VERSION 5.7 ;
  NOWIREEXTENSIONATPIN ON ;
  DIVIDERCHAR "/" ;
  BUSBITCHARS "[]" ;
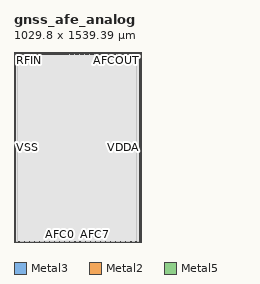
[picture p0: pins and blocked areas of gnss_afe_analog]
MACRO gnss_afe_analog
  CLASS BLOCK ;
  FOREIGN gnss_afe_analog ;
  ORIGIN 0.000 0.000 ;
  SIZE 1029.800 BY 1539.395 ;
  PIN VSS
    DIRECTION INOUT ;
    USE GROUND ;
    PORT
      LAYER Metal3 ;
        RECT 6.000 6.000 9.000 1533.395 ;
    END
    PORT
      LAYER Metal2 ;
        RECT 436.440 1533.295 445.940 1539.395 ;
    END
    PORT
      LAYER Metal2 ;
        RECT 423.290 1533.295 433.540 1539.395 ;
    END
    PORT
      LAYER Metal2 ;
        RECT 411.440 1533.295 421.690 1539.395 ;
    END
    PORT
      LAYER Metal2 ;
        RECT 397.910 1533.295 408.160 1539.395 ;
    END
    PORT
      LAYER Metal2 ;
        RECT 386.060 1533.295 396.310 1539.395 ;
    END
    PORT
      LAYER Metal2 ;
        RECT 373.660 1533.295 383.160 1539.395 ;
    END
    PORT
      LAYER Metal2 ;
        RECT 228.440 1533.295 237.940 1539.395 ;
    END
    PORT
      LAYER Metal2 ;
        RECT 215.290 1533.295 225.540 1539.395 ;
    END
    PORT
      LAYER Metal2 ;
        RECT 203.440 1533.295 213.690 1539.395 ;
    END
    PORT
      LAYER Metal2 ;
        RECT 189.910 1533.295 200.160 1539.395 ;
    END
    PORT
      LAYER Metal2 ;
        RECT 178.060 1533.295 188.310 1539.395 ;
    END
    PORT
      LAYER Metal2 ;
        RECT 165.660 1533.295 175.160 1539.395 ;
    END
    PORT
      LAYER Metal2 ;
        RECT 20.440 1533.295 29.940 1539.395 ;
    END
    PORT
      LAYER Metal2 ;
        RECT 7.290 1533.295 17.540 1539.395 ;
    END
    PORT
      LAYER Metal5 ;
        RECT 6.000 1530.395 1023.800 1533.395 ;
    END
  END VSS
  PIN VDDA
    DIRECTION INOUT ;
    USE POWER ;
    PORT
      LAYER Metal3 ;
        RECT 1020.800 6.000 1023.800 1533.395 ;
    END
    PORT
      LAYER Metal2 ;
        RECT 332.440 1524.295 341.940 1539.395 ;
    END
    PORT
      LAYER Metal2 ;
        RECT 319.290 1524.295 329.540 1539.395 ;
    END
    PORT
      LAYER Metal2 ;
        RECT 307.440 1524.295 317.690 1539.395 ;
    END
    PORT
      LAYER Metal2 ;
        RECT 293.910 1524.295 304.160 1539.395 ;
    END
    PORT
      LAYER Metal2 ;
        RECT 282.060 1524.295 292.310 1539.395 ;
    END
    PORT
      LAYER Metal2 ;
        RECT 269.660 1524.295 279.160 1539.395 ;
    END
    PORT
      LAYER Metal5 ;
        RECT 6.000 1521.395 45.500 1524.395 ;
    END
    PORT
      LAYER Metal5 ;
        RECT 56.500 1521.395 85.500 1524.395 ;
    END
    PORT
      LAYER Metal5 ;
        RECT 96.500 1521.395 125.500 1524.395 ;
    END
    PORT
      LAYER Metal5 ;
        RECT 136.500 1521.395 165.500 1524.395 ;
    END
    PORT
      LAYER Metal5 ;
        RECT 176.500 1521.395 205.500 1524.395 ;
    END
    PORT
      LAYER Metal5 ;
        RECT 216.500 1521.395 245.500 1524.395 ;
    END
    PORT
      LAYER Metal5 ;
        RECT 256.500 1521.395 285.500 1524.395 ;
    END
    PORT
      LAYER Metal5 ;
        RECT 296.500 1521.395 325.500 1524.395 ;
    END
    PORT
      LAYER Metal5 ;
        RECT 336.500 1521.395 365.500 1524.395 ;
    END
    PORT
      LAYER Metal5 ;
        RECT 376.500 1521.395 405.500 1524.395 ;
    END
    PORT
      LAYER Metal5 ;
        RECT 416.500 1521.395 445.500 1524.395 ;
    END
    PORT
      LAYER Metal5 ;
        RECT 456.500 1521.395 485.500 1524.395 ;
    END
    PORT
      LAYER Metal5 ;
        RECT 496.500 1521.395 525.500 1524.395 ;
    END
    PORT
      LAYER Metal5 ;
        RECT 536.500 1521.395 565.500 1524.395 ;
    END
    PORT
      LAYER Metal5 ;
        RECT 576.500 1521.395 605.500 1524.395 ;
    END
    PORT
      LAYER Metal5 ;
        RECT 616.500 1521.395 645.500 1524.395 ;
    END
    PORT
      LAYER Metal5 ;
        RECT 656.500 1521.395 665.500 1524.395 ;
    END
    PORT
      LAYER Metal5 ;
        RECT 676.500 1521.395 685.500 1524.395 ;
    END
    PORT
      LAYER Metal5 ;
        RECT 696.500 1521.395 725.500 1524.395 ;
    END
    PORT
      LAYER Metal5 ;
        RECT 736.500 1521.395 745.500 1524.395 ;
    END
    PORT
      LAYER Metal5 ;
        RECT 756.500 1521.395 765.500 1524.395 ;
    END
    PORT
      LAYER Metal5 ;
        RECT 776.500 1521.395 805.500 1524.395 ;
    END
    PORT
      LAYER Metal5 ;
        RECT 816.500 1521.395 825.500 1524.395 ;
    END
    PORT
      LAYER Metal5 ;
        RECT 836.500 1521.395 845.500 1524.395 ;
    END
    PORT
      LAYER Metal5 ;
        RECT 856.500 1521.395 885.500 1524.395 ;
    END
    PORT
      LAYER Metal5 ;
        RECT 896.500 1521.395 905.500 1524.395 ;
    END
    PORT
      LAYER Metal5 ;
        RECT 916.500 1521.395 925.500 1524.395 ;
    END
    PORT
      LAYER Metal5 ;
        RECT 936.500 1521.395 965.500 1524.395 ;
    END
    PORT
      LAYER Metal5 ;
        RECT 976.500 1521.395 985.500 1524.395 ;
    END
    PORT
      LAYER Metal5 ;
        RECT 996.500 1521.395 1023.800 1524.395 ;
    END
  END VDDA
  PIN RFIN
    DIRECTION INOUT ;
    USE SIGNAL ;
    ANTENNADIFFAREA 33.599998 ;
    PORT
      LAYER Metal2 ;
        RECT 75.640 1537.395 119.960 1539.395 ;
    END
  END RFIN
  PIN VDDV
    DIRECTION INOUT ;
    USE POWER ;
    PORT
      LAYER Metal2 ;
        RECT 540.440 1528.795 549.940 1539.395 ;
    END
    PORT
      LAYER Metal2 ;
        RECT 527.290 1528.795 537.540 1539.395 ;
    END
    PORT
      LAYER Metal2 ;
        RECT 515.440 1528.795 525.690 1539.395 ;
    END
    PORT
      LAYER Metal2 ;
        RECT 501.910 1528.795 512.160 1539.395 ;
    END
    PORT
      LAYER Metal2 ;
        RECT 490.060 1528.795 500.310 1539.395 ;
    END
    PORT
      LAYER Metal2 ;
        RECT 477.660 1528.795 487.160 1539.395 ;
    END
    PORT
      LAYER Metal5 ;
        RECT 6.000 1525.895 45.500 1528.895 ;
    END
    PORT
      LAYER Metal5 ;
        RECT 56.500 1525.895 85.500 1528.895 ;
    END
    PORT
      LAYER Metal5 ;
        RECT 96.500 1525.895 125.500 1528.895 ;
    END
    PORT
      LAYER Metal5 ;
        RECT 136.500 1525.895 165.500 1528.895 ;
    END
    PORT
      LAYER Metal5 ;
        RECT 176.500 1525.895 205.500 1528.895 ;
    END
    PORT
      LAYER Metal5 ;
        RECT 216.500 1525.895 245.500 1528.895 ;
    END
    PORT
      LAYER Metal5 ;
        RECT 256.500 1525.895 285.500 1528.895 ;
    END
    PORT
      LAYER Metal5 ;
        RECT 296.500 1525.895 325.500 1528.895 ;
    END
    PORT
      LAYER Metal5 ;
        RECT 336.500 1525.895 365.500 1528.895 ;
    END
    PORT
      LAYER Metal5 ;
        RECT 376.500 1525.895 405.500 1528.895 ;
    END
    PORT
      LAYER Metal5 ;
        RECT 416.500 1525.895 445.500 1528.895 ;
    END
    PORT
      LAYER Metal5 ;
        RECT 456.500 1525.895 485.500 1528.895 ;
    END
    PORT
      LAYER Metal5 ;
        RECT 496.500 1525.895 525.500 1528.895 ;
    END
    PORT
      LAYER Metal5 ;
        RECT 536.500 1525.895 565.500 1528.895 ;
    END
    PORT
      LAYER Metal5 ;
        RECT 576.500 1525.895 605.500 1528.895 ;
    END
    PORT
      LAYER Metal5 ;
        RECT 616.500 1525.895 645.500 1528.895 ;
    END
    PORT
      LAYER Metal5 ;
        RECT 656.500 1525.895 685.500 1528.895 ;
    END
    PORT
      LAYER Metal5 ;
        RECT 696.500 1525.895 725.500 1528.895 ;
    END
    PORT
      LAYER Metal5 ;
        RECT 736.500 1525.895 765.500 1528.895 ;
    END
    PORT
      LAYER Metal5 ;
        RECT 776.500 1525.895 805.500 1528.895 ;
    END
    PORT
      LAYER Metal5 ;
        RECT 816.500 1525.895 845.500 1528.895 ;
    END
    PORT
      LAYER Metal5 ;
        RECT 856.500 1525.895 885.500 1528.895 ;
    END
    PORT
      LAYER Metal5 ;
        RECT 896.500 1525.895 925.500 1528.895 ;
    END
    PORT
      LAYER Metal5 ;
        RECT 936.500 1525.895 965.500 1528.895 ;
    END
    PORT
      LAYER Metal5 ;
        RECT 976.500 1525.895 1023.800 1528.895 ;
    END
  END VDDV
  PIN REFIN
    DIRECTION INOUT ;
    USE SIGNAL ;
    PORT
      LAYER Metal2 ;
        RECT 1016.300 1537.395 1026.300 1539.395 ;
    END
  END REFIN
  PIN AFCOUT
    DIRECTION INOUT ;
    USE SIGNAL ;
    PORT
      LAYER Metal2 ;
        RECT 919.800 1537.395 929.800 1539.395 ;
    END
  END AFCOUT
  PIN VCTRL
    DIRECTION INOUT ;
    USE SIGNAL ;
    PORT
      LAYER Metal2 ;
        RECT 607.800 1535.395 617.800 1539.395 ;
    END
  END VCTRL
  PIN IG1A
    DIRECTION INOUT ;
    USE SIGNAL ;
    ANTENNAGATEAREA 11.200000 ;
    PORT
      LAYER Metal3 ;
        RECT 39.800 -0.100 40.800 0.900 ;
    END
  END IG1A
  PIN IG1B
    DIRECTION INOUT ;
    USE SIGNAL ;
    ANTENNAGATEAREA 22.400000 ;
    PORT
      LAYER Metal3 ;
        RECT 81.100 -0.100 82.100 0.900 ;
    END
  END IG1B
  PIN IG2A
    DIRECTION INOUT ;
    USE SIGNAL ;
    ANTENNAGATEAREA 11.200000 ;
    PORT
      LAYER Metal3 ;
        RECT 122.400 -0.100 123.400 0.900 ;
    END
  END IG2A
  PIN IG2B
    DIRECTION INOUT ;
    USE SIGNAL ;
    ANTENNAGATEAREA 22.400000 ;
    PORT
      LAYER Metal3 ;
        RECT 163.700 -0.100 164.700 0.900 ;
    END
  END IG2B
  PIN IG3A
    DIRECTION INOUT ;
    USE SIGNAL ;
    ANTENNAGATEAREA 11.200000 ;
    PORT
      LAYER Metal3 ;
        RECT 205.000 -0.100 206.000 0.900 ;
    END
  END IG3A
  PIN IG3B
    DIRECTION INOUT ;
    USE SIGNAL ;
    ANTENNAGATEAREA 22.400000 ;
    PORT
      LAYER Metal3 ;
        RECT 246.300 -0.100 247.300 0.900 ;
    END
  END IG3B
  PIN B0
    DIRECTION INOUT ;
    USE SIGNAL ;
    ANTENNAGATEAREA 0.840000 ;
    PORT
      LAYER Metal3 ;
        RECT 287.600 -0.100 288.600 0.900 ;
    END
  END B0
  PIN B1
    DIRECTION INOUT ;
    USE SIGNAL ;
    ANTENNAGATEAREA 0.840000 ;
    PORT
      LAYER Metal3 ;
        RECT 328.900 -0.100 329.900 0.900 ;
    END
  END B1
  PIN AFC0
    DIRECTION INOUT ;
    USE SIGNAL ;
    ANTENNAGATEAREA 0.840000 ;
    PORT
      LAYER Metal3 ;
        RECT 369.500 -0.100 370.500 0.900 ;
    END
  END AFC0
  PIN AFC1
    DIRECTION INOUT ;
    USE SIGNAL ;
    ANTENNAGATEAREA 0.840000 ;
    PORT
      LAYER Metal3 ;
        RECT 410.800 -0.100 411.800 0.900 ;
    END
  END AFC1
  PIN AFC2
    DIRECTION INOUT ;
    USE SIGNAL ;
    ANTENNAGATEAREA 0.840000 ;
    PORT
      LAYER Metal3 ;
        RECT 452.100 -0.100 453.100 0.900 ;
    END
  END AFC2
  PIN AFC3
    DIRECTION INOUT ;
    USE SIGNAL ;
    ANTENNAGATEAREA 0.840000 ;
    PORT
      LAYER Metal3 ;
        RECT 493.400 -0.100 494.400 0.900 ;
    END
  END AFC3
  PIN AFC4
    DIRECTION INOUT ;
    USE SIGNAL ;
    ANTENNAGATEAREA 0.840000 ;
    PORT
      LAYER Metal3 ;
        RECT 534.700 -0.100 535.700 0.900 ;
    END
  END AFC4
  PIN AFC5
    DIRECTION INOUT ;
    USE SIGNAL ;
    ANTENNAGATEAREA 0.840000 ;
    PORT
      LAYER Metal3 ;
        RECT 576.000 -0.100 577.000 0.900 ;
    END
  END AFC5
  PIN AFC6
    DIRECTION INOUT ;
    USE SIGNAL ;
    ANTENNAGATEAREA 0.840000 ;
    PORT
      LAYER Metal3 ;
        RECT 617.300 -0.100 618.300 0.900 ;
    END
  END AFC6
  PIN AFC7
    DIRECTION INOUT ;
    USE SIGNAL ;
    ANTENNAGATEAREA 0.840000 ;
    PORT
      LAYER Metal3 ;
        RECT 658.600 -0.100 659.600 0.900 ;
    END
  END AFC7
  PIN ICP2
    DIRECTION INOUT ;
    USE SIGNAL ;
    ANTENNAGATEAREA 1.960000 ;
    PORT
      LAYER Metal3 ;
        RECT 699.200 -0.100 700.200 0.900 ;
    END
  END ICP2
  PIN BWK
    DIRECTION INOUT ;
    USE SIGNAL ;
    ANTENNAGATEAREA 17.920000 ;
    PORT
      LAYER Metal3 ;
        RECT 740.500 -0.100 741.500 0.900 ;
    END
  END BWK
  PIN BWN
    DIRECTION INOUT ;
    USE SIGNAL ;
    ANTENNAGATEAREA 17.920000 ;
    PORT
      LAYER Metal3 ;
        RECT 781.800 -0.100 782.800 0.900 ;
    END
  END BWN
  PIN I_SIGN
    DIRECTION INOUT ;
    USE SIGNAL ;
    ANTENNAGATEAREA 1.400000 ;
    ANTENNADIFFAREA 2.670000 ;
    PORT
      LAYER Metal3 ;
        RECT 823.100 -0.100 824.100 0.900 ;
    END
  END I_SIGN
  PIN I_MAG
    DIRECTION INOUT ;
    USE SIGNAL ;
    ANTENNADIFFAREA 2.670000 ;
    PORT
      LAYER Metal3 ;
        RECT 864.400 -0.100 865.400 0.900 ;
    END
  END I_MAG
  PIN Q_SIGN
    DIRECTION INOUT ;
    USE SIGNAL ;
    ANTENNAGATEAREA 1.400000 ;
    ANTENNADIFFAREA 2.670000 ;
    PORT
      LAYER Metal3 ;
        RECT 905.700 -0.100 906.700 0.900 ;
    END
  END Q_SIGN
  PIN Q_MAG
    DIRECTION INOUT ;
    USE SIGNAL ;
    ANTENNADIFFAREA 2.670000 ;
    PORT
      LAYER Metal3 ;
        RECT 947.000 -0.100 948.000 0.900 ;
    END
  END Q_MAG
  PIN CLKOUT
    DIRECTION INOUT ;
    USE SIGNAL ;
    ANTENNADIFFAREA 4.770000 ;
    PORT
      LAYER Metal3 ;
        RECT 988.300 -0.100 989.300 0.900 ;
    END
  END CLKOUT
  OBS
      LAYER Nwell ;
        RECT 28.240 16.260 997.780 1509.395 ;
      LAYER Metal1 ;
        RECT 28.505 16.445 997.595 1509.210 ;
      LAYER Metal2 ;
        RECT 17.840 1532.995 20.140 1537.790 ;
        RECT 30.240 1537.095 75.340 1537.790 ;
        RECT 120.260 1537.095 165.360 1537.790 ;
        RECT 30.240 1532.995 165.360 1537.095 ;
        RECT 175.460 1532.995 177.760 1537.790 ;
        RECT 188.610 1532.995 189.610 1537.790 ;
        RECT 200.460 1532.995 203.140 1537.790 ;
        RECT 213.990 1532.995 214.990 1537.790 ;
        RECT 225.840 1532.995 228.140 1537.790 ;
        RECT 238.240 1532.995 269.360 1537.790 ;
        RECT 7.290 1523.995 269.360 1532.995 ;
        RECT 279.460 1523.995 281.760 1537.790 ;
        RECT 292.610 1523.995 293.610 1537.790 ;
        RECT 304.460 1523.995 307.140 1537.790 ;
        RECT 317.990 1523.995 318.990 1537.790 ;
        RECT 329.840 1523.995 332.140 1537.790 ;
        RECT 342.240 1532.995 373.360 1537.790 ;
        RECT 383.460 1532.995 385.760 1537.790 ;
        RECT 396.610 1532.995 397.610 1537.790 ;
        RECT 408.460 1532.995 411.140 1537.790 ;
        RECT 421.990 1532.995 422.990 1537.790 ;
        RECT 433.840 1532.995 436.140 1537.790 ;
        RECT 446.240 1532.995 477.360 1537.790 ;
        RECT 342.240 1528.495 477.360 1532.995 ;
        RECT 487.460 1528.495 489.760 1537.790 ;
        RECT 500.610 1528.495 501.610 1537.790 ;
        RECT 512.460 1528.495 515.140 1537.790 ;
        RECT 525.990 1528.495 526.990 1537.790 ;
        RECT 537.840 1528.495 540.140 1537.790 ;
        RECT 550.240 1535.095 607.500 1537.790 ;
        RECT 618.100 1537.095 919.500 1537.790 ;
        RECT 930.100 1537.095 1016.000 1537.790 ;
        RECT 618.100 1535.095 1026.300 1537.095 ;
        RECT 550.240 1528.495 1026.300 1535.095 ;
        RECT 342.240 1523.995 1026.300 1528.495 ;
        RECT 7.290 0.210 1026.300 1523.995 ;
      LAYER Metal3 ;
        RECT 9.000 1533.695 1016.990 1539.150 ;
        RECT 9.300 5.700 1016.990 1533.695 ;
        RECT 9.000 1.200 1016.990 5.700 ;
        RECT 9.000 0.210 39.500 1.200 ;
        RECT 41.100 0.210 80.800 1.200 ;
        RECT 82.400 0.210 122.100 1.200 ;
        RECT 123.700 0.210 163.400 1.200 ;
        RECT 165.000 0.210 204.700 1.200 ;
        RECT 206.300 0.210 246.000 1.200 ;
        RECT 247.600 0.210 287.300 1.200 ;
        RECT 288.900 0.210 328.600 1.200 ;
        RECT 330.200 0.210 369.200 1.200 ;
        RECT 370.800 0.210 410.500 1.200 ;
        RECT 412.100 0.210 451.800 1.200 ;
        RECT 453.400 0.210 493.100 1.200 ;
        RECT 494.700 0.210 534.400 1.200 ;
        RECT 536.000 0.210 575.700 1.200 ;
        RECT 577.300 0.210 617.000 1.200 ;
        RECT 618.600 0.210 658.300 1.200 ;
        RECT 659.900 0.210 698.900 1.200 ;
        RECT 700.500 0.210 740.200 1.200 ;
        RECT 741.800 0.210 781.500 1.200 ;
        RECT 783.100 0.210 822.800 1.200 ;
        RECT 824.400 0.210 864.100 1.200 ;
        RECT 865.700 0.210 905.400 1.200 ;
        RECT 907.000 0.210 946.700 1.200 ;
        RECT 948.300 0.210 988.000 1.200 ;
        RECT 989.600 0.210 1016.990 1.200 ;
      LAYER Metal4 ;
        RECT 6.000 1.610 1023.800 1533.395 ;
      LAYER Metal5 ;
        RECT 26.000 1529.495 996.000 1529.795 ;
        RECT 46.100 1525.295 55.900 1529.495 ;
        RECT 86.100 1525.295 95.900 1529.495 ;
        RECT 126.100 1525.295 135.900 1529.495 ;
        RECT 166.100 1525.295 175.900 1529.495 ;
        RECT 206.100 1525.295 215.900 1529.495 ;
        RECT 246.100 1525.295 255.900 1529.495 ;
        RECT 286.100 1525.295 295.900 1529.495 ;
        RECT 326.100 1525.295 335.900 1529.495 ;
        RECT 366.100 1525.295 375.900 1529.495 ;
        RECT 406.100 1525.295 415.900 1529.495 ;
        RECT 446.100 1525.295 455.900 1529.495 ;
        RECT 486.100 1525.295 495.900 1529.495 ;
        RECT 526.100 1525.295 535.900 1529.495 ;
        RECT 566.100 1525.295 575.900 1529.495 ;
        RECT 606.100 1525.295 615.900 1529.495 ;
        RECT 646.100 1525.295 655.900 1529.495 ;
        RECT 686.100 1525.295 695.900 1529.495 ;
        RECT 726.100 1525.295 735.900 1529.495 ;
        RECT 766.100 1525.295 775.900 1529.495 ;
        RECT 806.100 1525.295 815.900 1529.495 ;
        RECT 846.100 1525.295 855.900 1529.495 ;
        RECT 886.100 1525.295 895.900 1529.495 ;
        RECT 926.100 1525.295 935.900 1529.495 ;
        RECT 966.100 1525.295 975.900 1529.495 ;
        RECT 26.000 1524.995 996.000 1525.295 ;
        RECT 46.100 1520.795 55.900 1524.995 ;
        RECT 86.100 1520.795 95.900 1524.995 ;
        RECT 126.100 1520.795 135.900 1524.995 ;
        RECT 166.100 1520.795 175.900 1524.995 ;
        RECT 206.100 1520.795 215.900 1524.995 ;
        RECT 246.100 1520.795 255.900 1524.995 ;
        RECT 286.100 1520.795 295.900 1524.995 ;
        RECT 326.100 1520.795 335.900 1524.995 ;
        RECT 366.100 1520.795 375.900 1524.995 ;
        RECT 406.100 1520.795 415.900 1524.995 ;
        RECT 446.100 1520.795 455.900 1524.995 ;
        RECT 486.100 1520.795 495.900 1524.995 ;
        RECT 526.100 1520.795 535.900 1524.995 ;
        RECT 566.100 1520.795 575.900 1524.995 ;
        RECT 606.100 1520.795 615.900 1524.995 ;
        RECT 646.100 1520.795 655.900 1524.995 ;
        RECT 666.100 1520.795 675.900 1524.995 ;
        RECT 686.100 1520.795 695.900 1524.995 ;
        RECT 726.100 1520.795 735.900 1524.995 ;
        RECT 746.100 1520.795 755.900 1524.995 ;
        RECT 766.100 1520.795 775.900 1524.995 ;
        RECT 806.100 1520.795 815.900 1524.995 ;
        RECT 826.100 1520.795 835.900 1524.995 ;
        RECT 846.100 1520.795 855.900 1524.995 ;
        RECT 886.100 1520.795 895.900 1524.995 ;
        RECT 906.100 1520.795 915.900 1524.995 ;
        RECT 926.100 1520.795 935.900 1524.995 ;
        RECT 966.100 1520.795 975.900 1524.995 ;
        RECT 986.100 1520.795 995.900 1524.995 ;
        RECT 26.000 6.000 996.000 1520.795 ;
  END
END gnss_afe_analog
END LIBRARY

